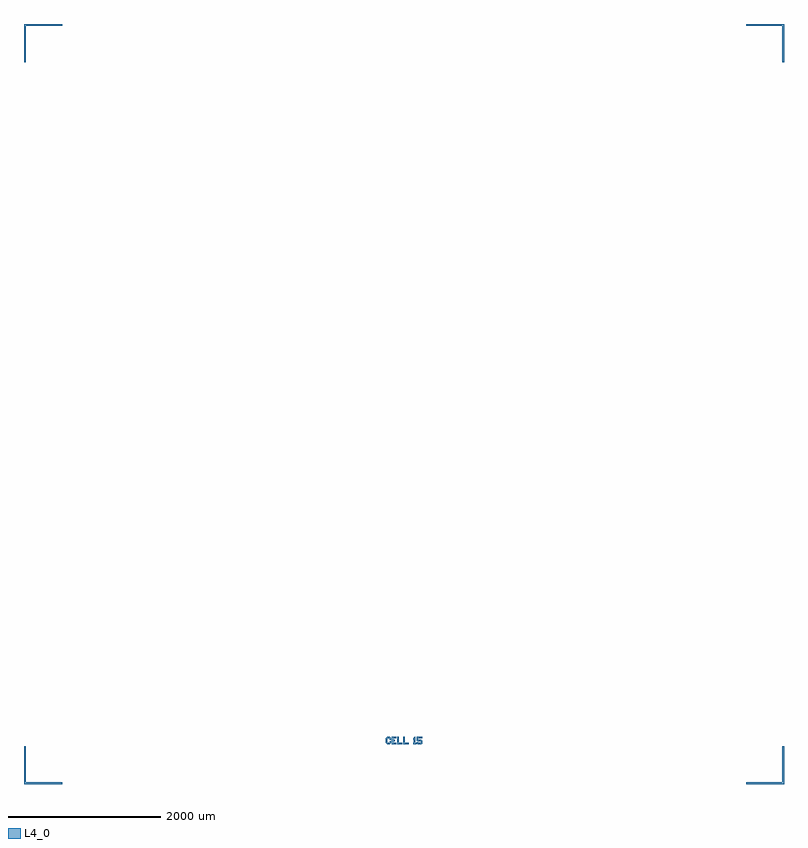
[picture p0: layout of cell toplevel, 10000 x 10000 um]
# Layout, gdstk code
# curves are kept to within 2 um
import gdstk
lib = gdstk.Library(unit=1e-6, precision=1e-09)
def P(c, l, *ps):  # polygons
    for p in ps: c.add(gdstk.Polygon(p, *l))
L4_0 = (4, 0)

toplevel = lib.new_cell('toplevel')
P(toplevel, L4_0, [(5000,5000),(5000,4500),(4980,4500),(4980,4980),(4500,4980),(4500,5000)],
  [(-5000,5000),(-5000,4500),(-4980,4500),(-4980,4980),(-4500,4980),(-4500,5000)],
  [(5000,-5000),(5000,-4500),(4980,-4500),(4980,-4980),(4500,-4980),(4500,-5000)],
  [(-5000,-5000),(-5000,-4500),(-4980,-4500),(-4980,-4980),(-4500,-4980),(-4500,-5000)],
  [(-220,-4480),(-240,-4460),(-240,-4400),(-220,-4380),(-190,-4380),(-170,-4400),(-170,-4420),(-190,-4420),(-190,-4410),(-200,-4400),(-210,-4400),(-220,-4410),(-220,-4450),(-210,-4460),(-200,-4460),(-190,-4450),(-190,-4440),(-170,-4440),(-170,-4460),(-190,-4480)],
  [(-100,-4380),(-100,-4400),(-140,-4400),(-140,-4420),(-120,-4420),(-120,-4440),(-140,-4440),(-140,-4460),(-100,-4460),(-100,-4480),(-160,-4480),(-160,-4380),(-100,-4380)],
  [(-90,-4380),(-70,-4380),(-70,-4460),(-20,-4460),(-20,-4480),(-90,-4480),(-90,-4380)],
  [(-10,-4380),(10,-4380),(10,-4460),(60,-4460),(60,-4480),(-10,-4480),(-10,-4380)],
  [(130,-4420),(120,-4420),(120,-4400),(140,-4380),(150,-4380),(150,-4460),(160,-4460),(160,-4480),(120,-4480),(120,-4460),(130,-4460)],
  [(240,-4400),(190,-4400),(190,-4420),(230,-4420),(240,-4430),(240,-4470),(230,-4480),(180,-4480),(170,-4470),(170,-4450),(190,-4450),(190,-4460),(220,-4460),(220,-4440),(180,-4440),(170,-4430),(170,-4380),(240,-4380)])

lib.write_gds('toplevel.gds')
